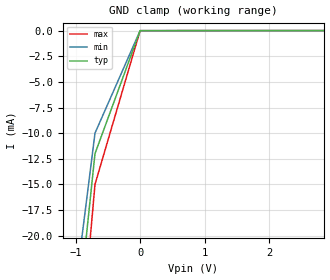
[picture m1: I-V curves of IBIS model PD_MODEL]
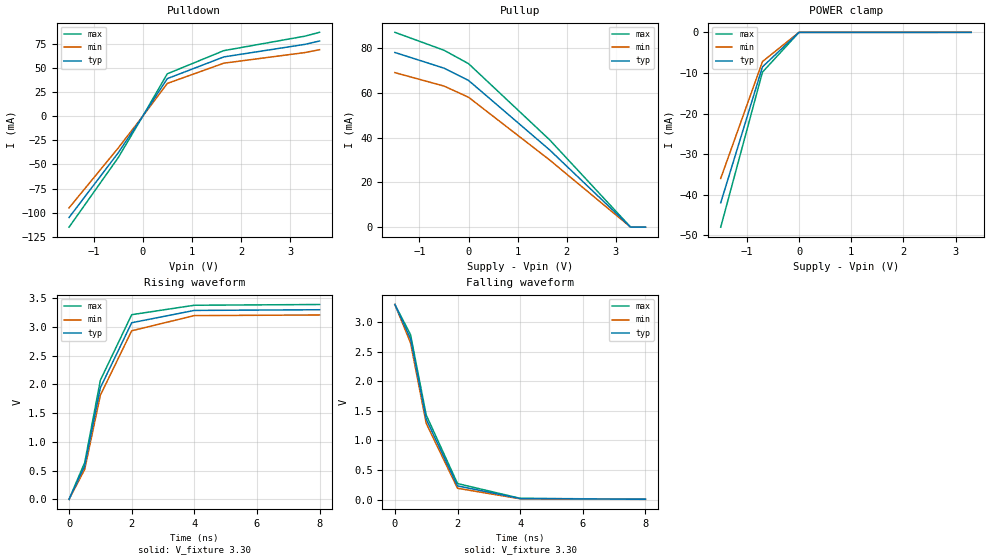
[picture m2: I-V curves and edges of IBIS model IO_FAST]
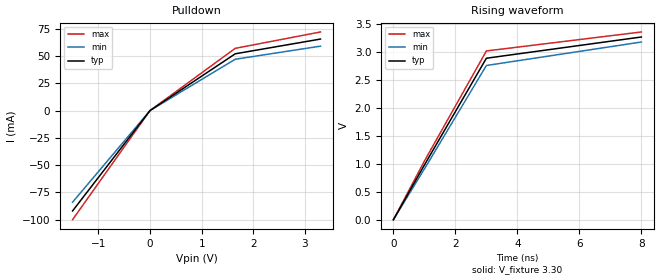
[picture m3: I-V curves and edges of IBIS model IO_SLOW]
| IBIS sample fixture for rfauto (tests/unit/fixtures/ibis/sample.ibs)
| Seat Q-X46 (aurora_q, 2026-11-07). Synthetic shape data -- NOT a real
| buffer. Covers: header keywords, component/manufacturer, package
| typ-min-max triples, pin table (GND/VDD/NC rows + R_pin/L_pin/C_pin),
| model selector, three models (Input with GND clamp only; Output with
| 3 IV tables + ramp + rising/falling waveforms; Output with pulldown
| and rising waveform only), and one unknown keyword ([OEM]) for the
| warning path. All numbers are fixture demonstration values.
[IBIS Ver]  3.2
[File Name] sample.ibs
[File Rev]  1.1
[Date]   2026-11-07
[Source]   rfauto fixture
[OEM]   synthetic-fixture
[Component] SAMPLE_SOC
[Manufacturer] rfauto
[Package]
R_pkg   4.50   3.80   5.20
L_pkg   2.10nH   1.80nH   2.40nH
C_pkg   1.10pF   0.90pF   1.30pF
[Pin]
| signal_name  model_name  R_pin  L_pin   C_pin
1   GND
2   VDD
3   IO_A0   PD_MODEL   0.30   1.10nH   0.60pF
4   IO_A1   IO_SEL   0.35   1.20nH   0.65pF
5   IO_A2   IO_FAST   0.40   1.30nH   0.70pF
6   NC
[Model Selector] IO_SEL
IO_FAST   Fast corner output model
IO_SLOW   Slow corner output model
| Models and submodels in the file (3): PD_MODEL (Input), IO_FAST (Output), IO_SLOW (Output)
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[Model] PD_MODEL
Model_type  Input
Vinl = 0.8V
Vinh = 2.0V
C_comp   1.80pF   1.50pF   2.10pF
GND_clamp_reference 0V
[GND Clamp]
| Voltage  I(typ)   I(min)   I(max)
-1.5V     -60mA      -50mA      -72mA
-700mV    -12mA      -10mA      -15mA
0V        0A         0A         0A
350mV     900nA      700nA      1.2uA
700mV     6.5uA      5uA        8uA
3.3V      8.5uA      7uA        10uA
[Model] IO_FAST
Model_type  Output
Polarity   Non-Inverting
Enable   Active-High
Vinl = 0.8V
Vinh = 2.0V
Vmeas = 1.65V
C_comp   2.20pF   1.90pF   2.50pF
Voltage_range   3.30V   3.00V   3.60V
GND_clamp_reference 0V
POWER_clamp_reference 3.3V
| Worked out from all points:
|   slope of the pulldown table from 0 to 0.3 V, typ, clamps not added: 12.8 ohm
|   slope of the pullup table from 0 to 0.3 V, typ, clamps not added: 53.2 ohm
|   rising waveform, V_fixture 3.30: 20-80 % time 1.09ns typ, 1.13ns min, 1.05ns max; typ from 0 V to 3.3 V
|   falling waveform, V_fixture 3.30: 20-80 % time 1.09ns typ, 1.07ns min, 1.11ns max; typ from 3.3 V to 0.004 V
[Pulldown]
| Voltage  I(typ)   I(min)   I(max)
-1.5V     -105mA     -95mA      -115mA
-500mV    -38mA      -33mA      -43mA
0V        0A         0A         0A
500mV     39mA       34mA       44mA
1.65V     61.5mA     55mA       68mA
3.3V      74.5mA     66mA       83mA
3.6V      78mA       69mA       87mA
[Pullup]
| Voltage  I(typ)   I(min)   I(max)
-1.5V     78mA       69mA       87mA
-500mV    71mA       63mA       79mA
0V        65.5mA     58mA       73mA
1.65V     34.5mA     30mA       39mA
3.3V      0A         0A         0A
3.6V      -6.5uA     -5uA       -8uA
[POWER Clamp]
| Voltage  I(typ)   I(min)   I(max)
-1.5V     -42mA      -36mA      -48mA
-700mV    -8.5mA     -7.2mA     -9.8mA
0V        0A         0A         0A
1.65V     2.5uA      2uA        3uA
3.3V      8.5uA      7uA        10uA
[Ramp]
Ramp_load = 50 Ohm
Ramp_dR   2.240   2.050   2.430
Ramp_dF   2.180   1.990   2.370
[Rising Waveform]
R_dut = 50.0 Ohm
C_dut = 10.0pF
L_dut = 1.0nH
V_fixture = 3.30
V_fixture_min = 3.00
V_fixture_max = 3.60
| time   V(typ)   V(min)   V(max)
0s        0V         0V         0V
500ps     580mV      520mV      640mV
1ns       1.94V      1.81V      2.07V
2ns       3.07V      2.93V      3.21V
4ns       3.284V     3.194V     3.374V
8ns       3.296V     3.205V     3.387V
[Falling Waveform]
R_dut = 50.0 Ohm
C_dut = 10.0pF
L_dut = 1.0nH
V_fixture = 3.30
| time   V(typ)   V(min)   V(max)
0s        3.3V       3.3V       3.3V
500ps     2.72V      2.65V      2.79V
1ns       1.36V      1.29V      1.43V
2ns       230mV      190mV      270mV
4ns       16mV       12mV       20mV
8ns       4mV        3mV        5mV
[Model] IO_SLOW
Model_type  Output
Polarity   Non-Inverting
Enable   Active-High
Vinl = 0.8V
Vinh = 2.0V
C_comp   2.20pF   1.90pF   2.50pF
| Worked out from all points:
|   slope of the pulldown table from 0 to 0.3 V, typ, clamps not added: 31.7 ohm
|   rising waveform, V_fixture 3.30: 20-80 % time 2.05ns typ, 2.07ns min, 2.02ns max; typ from 0 V to 3.27 V
[Pulldown]
| Voltage  I(typ)   I(min)   I(max)
-1.5V     -92mA      -84mA      -100mA
0V        0A         0A         0A
1.65V     52mA       47mA       57mA
3.3V      65.5mA     59mA       72mA
[Rising Waveform]
R_dut = 50.0 Ohm
C_dut = 10.0pF
L_dut = 1.0nH
V_fixture = 3.30
| time   V(typ)   V(min)   V(max)
0s        0V         0V         0V
1ns       980mV      910mV      1.05V
3ns       2.89V      2.76V      3.02V
8ns       3.27V      3.18V      3.36V
